VERSION 5.8 ;
BUSBITCHARS "[]" ;
DIVIDERCHAR "/" ;
CLEARANCEMEASURE EUCLIDEAN ;

SITE coresite_DH_P
    SIZE 0.0450 BY 0.2880 ;
    CLASS CORE ;
    SYMMETRY X Y ;
END coresite_DH_P

SITE coresite_DH_N
    SIZE 0.0450 BY 0.2880 ;
    CLASS CORE ;
    SYMMETRY X Y ;
END coresite_DH_N

SITE coresite
    SIZE 0.0450 BY 0.1440 ;
    CLASS CORE ;
    SYMMETRY X Y ;
END coresite

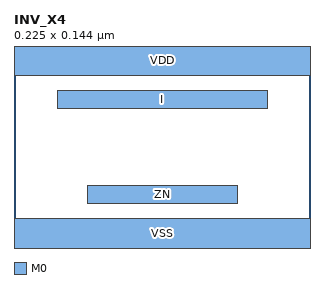
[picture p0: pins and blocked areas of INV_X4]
MACRO INV_X4
  CLASS CORE ;
  ORIGIN 0 0 ;
  FOREIGN INV_X4 0 0 ;
  SIZE 0.2250 BY 0.1440 ;
  SYMMETRY X Y ;
  SITE coresite ;
  PIN ZN
    DIRECTION OUTPUT ;
    USE SIGNAL ;
    PORT
      LAYER M0 ;
        RECT 0.0555 0.0430 0.1695 0.0290 ;
    END
  END ZN
  PIN I
    DIRECTION INPUT ;
    USE SIGNAL ;
    PORT
      LAYER M0 ;
        RECT 0.0330 0.1150 0.1920 0.1010 ;
    END
  END I
  PIN VDD
    DIRECTION INOUT ;
    USE POWER ;
    SHAPE ABUTMENT ;
    PORT
      LAYER M0 ;
        RECT 0.0000 0.1260 0.2250 0.1620 ;
    END
  END VDD
  PIN VSS
    DIRECTION INOUT ;
    USE GROUND ;
    SHAPE ABUTMENT ;
    PORT
      LAYER M0 ;
        RECT 0.0000 -0.0180 0.2250 0.0180 ;
    END
  END VSS
END INV_X4

END LIBRARY
